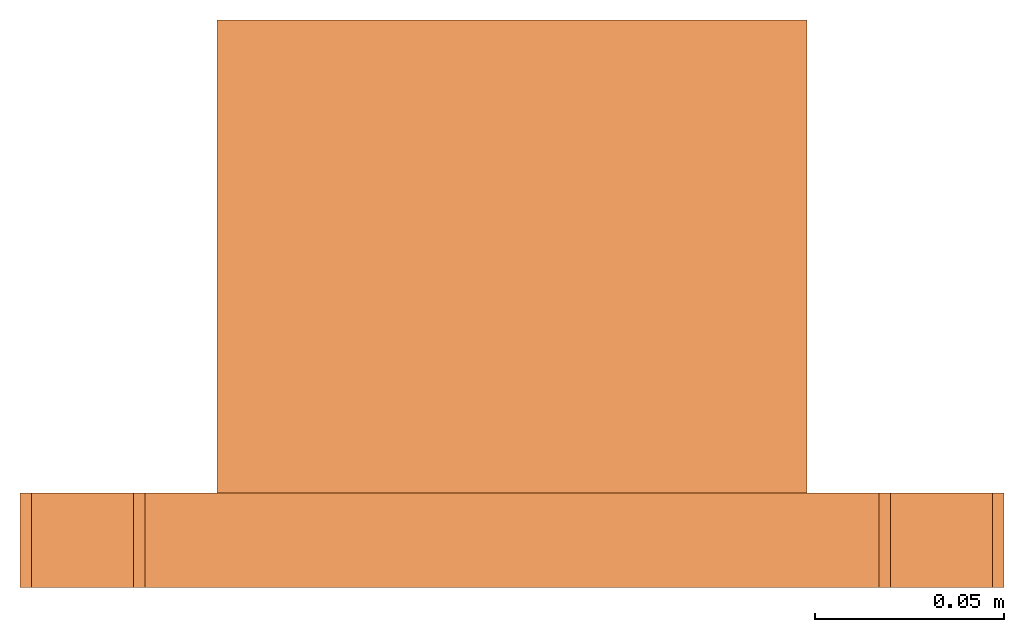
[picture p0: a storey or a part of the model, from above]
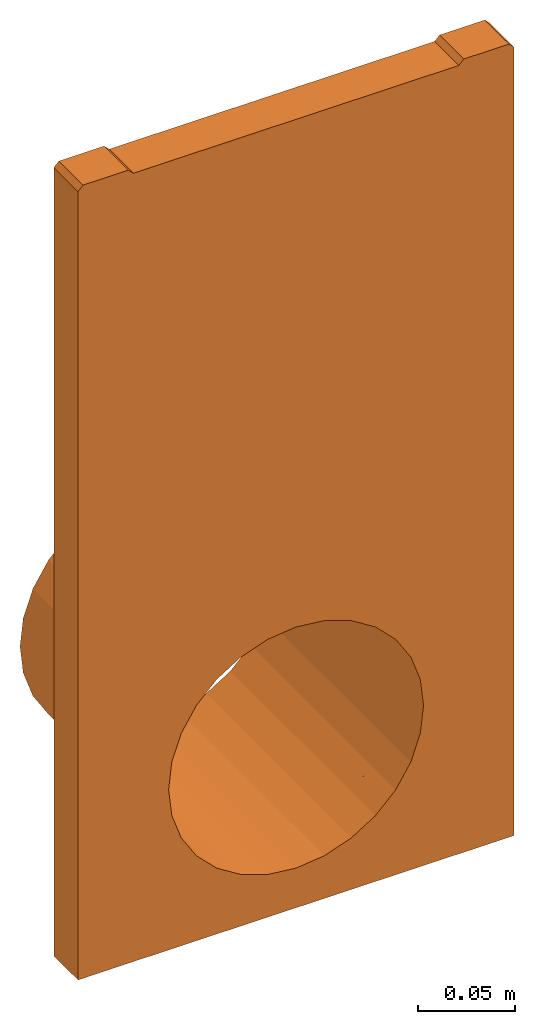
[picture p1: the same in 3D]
Properties of the parts of a building model (IFC2X3)

# File
Description: ViewDefinition [CoordinationView]
File name: 33308 - PD200 F 308 Inlet outlet endcap.ifc
Time: 2013-10-11T12:59:09
Written by: Autodesk Revit 2013
Made in: 20120221_2030(x64)

# IfcProject, Project Number
LongName: Project Name; Phase: Project Status

# IfcSite, Default
RefLatitude: 42, 21, 30, 344238; RefLongitude: -71, -3, -35, -194702; RefElevation: 0 mm

# IfcBuilding
Pset_BuildingCommon - NumberOfStoreys: 2
Other - Project Number: Project Number; Project Address: Enter address here; Project Name: Project Name; Project Issue Date: Issue Date; Client Name: Owner; Project Status: Project Status

# IfcBuildingStorey (2)
Constraints - Elevation Base: 0
Graphics - Symbol: M_Level Head - Circle: M_Level Head - Circle; Line Weight: 1; Symbol at End 1 Default: no; Symbol at End 2 Default: yes; Line Pattern: Center; Color: 0
Identity Data - Building Story: yes; Structural: no
Dimensions - Computation Height: 0 mm
Name | LongName = Name | Elevation (mm) = Constraints, Elevation (mm)
B.O. Footing | B.O. Footing | -4600
T.O. Footing | T.O. Footing | -4300

# IfcBuildingElementProxy: 33308 - PD200 F 308 Inlet/outlet endcap, Civil-Drainage-Channel-ACO-RoadDrain 200:33308 - PD200 F 308 Inlet/outlet endcap:33308 - PD200 F 308 Inlet/outlet endcap:309971
In: B.O. Footing
Material: Phenolic Resin, Acetal Resin, Black
Other - Revision: 1; CreatedBy: www.aco.co.uk
Dimensions - Straight Void Start: 0 mm; Void Depth: -500 mm; Invert Depth.: 325 mm; I/O End Cap Void: 228 mm; Total Depth: 500 mm; Pipe Depth: 399 mm; Custom Void Length: 0 mm; Straight Void Length: 25 mm; Volume: 2902322 mm3; Length: 500 mm
Construction - Inlet Outlet end cap: yes; Channel 260mm Wide: no; Access unit: no; Closing End Cap: no
Phasing - Phase Created: Phase 1
Constraints - Level: Level: T.O. Footing; Moves With Nearby Elements: no
Pset_BuildingElementProxyCommon - Reference: 33308 - PD200 F 308 Inlet/outlet endcap
Identity Data - Model Description: Monolithic Channel drainage system; URL: www.aco.co.uk; Maintenance guidelines: http://www.aco.co.uk/download.php?id=256; e-mail Sales: customersupport@aco.co.uk; Type Comments: ACO RoadDrain PD200 F 308 Inlet/Outlet End Cap; Assembly Description: Rain Water Drainage; OmniClass Title: Rainwater Removal; Product brochure: http://www.aco.co.uk/download.php?id=256; Cost: 0; OmniClass Number: 23.70.50.24; Fax: +44 (0)1462 815895; Watermark 1: This file is the property of ACO Technologies PLC; Installation guidelines: http://www.aco.co.uk/download.php?id=256; e-mail Technical: technical@aco.co.uk; Watermarked With: BIM Manager Premium Suite; Product Code: 33308; Address: ACO Business Park, Hitchin Road, Shefford, Bedfordshire, United Kingdom SG17 5TE; Watermarked By: www.aco.co.uk; Model: ACO RoadDrain 200 PD200F; Manufacturer: ACO Technologies plc - ACO Water Management Division; Product Page URL: http://www.aco.co.uk/product_detail.php?id=21; Price: POA - contact ACO; Watermark 2: This file is water marked and users are prohibited to reproduce, adapt, distribute this information; Telephone: +44 (0)1462 816666; Assembly Code: D2040
Green Building Properties - End Cap Recycled Material Content: 20% minimum; Channel Recyclable: N/A; End Cap Recyclable: Fully recyclable; Access Cover/Frame Recycled Material Content: N/A; Access Cover/Frame Recyclable: N/A; Channel Recycled Material Content: N/A
Data - Installation - Concrete Grade: N/A; Connection Pipe O.D: Ø160mm; Load Class: N/A; Hydraulic Performance: N/A; ACO Hydraulic Design Software: N/A; Invert Depth: N/A; Product Standard: N/A; Channel C.S.A: N/A; Product Dimensions: 25mm x 260mm x 500mm (LxWxH); Product Weight: 5.2 kg; Concrete Surround Volume - Load Class F 900 - Concrete Pavement: N/A
General - SerialNumber: 0.000000; TagNumber: 0.000000
Materials and Finishes - Channel Material: N/A; End Cap Colour: Black; Connection Pipe Colour: Brown; Access Cover/Frame Finish: N/A; End Cap Material: Vienite® Synthetic Resin Concrete; Grating Colour: N/A; Access Cover/Frame Colour: N/A; Channel Colour: N/A; Access Cover/Frame Material: N/A; Grating Finish: N/A; Grating Material: N/A; Connection Pipe Material: PVCu

# IfcOpeningElement: Recess
In: T.O. Footing
Dimensions - Area: 26010000 mm2; Volume: 40309861426 mm3; Thickness: 1550 mm; Perimeter: 20400 mm
Constraints - Height Offset From Level: 0 mm; Level: Level: T.O. Footing; Room Bounding: yes; Related to Mass: no
Structural - Enable Analytical Model: no; Structural: no
Phasing - Phase Created: Phase 1
Analytical Properties - Thermal Resistance (R): 1.79211; Heat Transfer Coefficient (U): 0.558; Thermal mass: 2039700; Absorptance: 0.1; Roughness: 1
Materials and Finishes - Structural Material: Grass
Construction - Function: 0; Default Thickness: 1550 mm
Graphics - Coarse Scale Fill Color: 0

# IfcSlab: Floor:Generic Floor - 400mm, Floor:Generic Floor - 400mm:136436
In: T.O. Footing
PredefinedType: FLOOR; Material: Grass 50 mm, Earth 1500 mm
Dimensions - Area: 26010000 mm2; Volume: 40309861426 mm3; Thickness: 1550 mm; Perimeter: 20400 mm
Constraints - Height Offset From Level: 0 mm; Level: Level: T.O. Footing; Room Bounding: yes; Related to Mass: no
Structural - Enable Analytical Model: no; Structural: no
Phasing - Phase Created: Phase 1
Pset_SlabCommon - Reference: Generic Floor - 400mm; IsExternal: no; LoadBearing: yes
Analytical Properties - Thermal Resistance (R): 1.79211; Heat Transfer Coefficient (U): 0.558; Thermal mass: 2039700; Absorptance: 0.1; Roughness: 1
Materials and Finishes - Structural Material: Grass
Construction - Function: 0; Default Thickness: 1550 mm
Graphics - Coarse Scale Fill Color: 0
